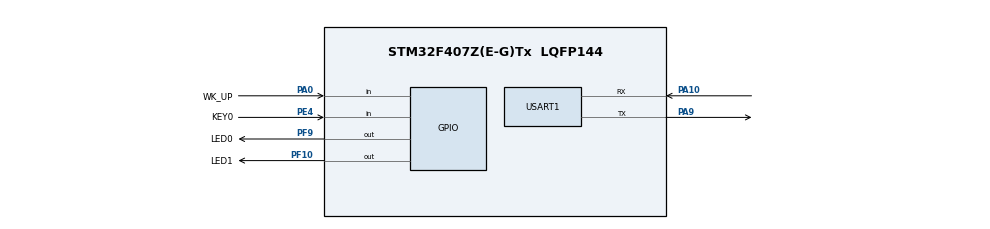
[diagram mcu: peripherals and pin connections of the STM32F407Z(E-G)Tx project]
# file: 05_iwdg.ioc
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IWDG.Prescaler=IWDG_PRESCALER_64
IWDG.Reload=500
Mcu.Family=STM32F4
Mcu.Name=STM32F407Z(E-G)Tx
Mcu.Package=LQFP144
NVIC.PriorityGroup=NVIC_PRIORITYGROUP_2
NVIC.USART1_IRQn=true\:2\:2\:true\:false\:true\:true\:true\:true
PA0-WKUP.GPIO_Label=WK_UP
PA0-WKUP.GPIO_PuPd=GPIO_PULLDOWN
PA0-WKUP.Signal=GPIO_Input
PA10.GPIO_PuPd=GPIO_PULLUP
PA10.Mode=Asynchronous
PA10.Signal=USART1_RX
PA13.Mode=Serial_Wire
PA13.Signal=SYS_JTMS-SWDIO
PA14.Mode=Serial_Wire
PA14.Signal=SYS_JTCK-SWCLK
PA9.GPIO_PuPd=GPIO_PULLUP
PA9.Mode=Asynchronous
PA9.Signal=USART1_TX
PC14-OSC32_IN.Mode=LSE-External-Oscillator
PC14-OSC32_IN.Signal=RCC_OSC32_IN
PC15-OSC32_OUT.Mode=LSE-External-Oscillator
PC15-OSC32_OUT.Signal=RCC_OSC32_OUT
PE4.GPIO_Label=KEY0
PE4.GPIO_PuPd=GPIO_PULLDOWN
PE4.Signal=GPIO_Input
PF10.GPIO_Label=LED1
PF10.GPIO_PuPd=GPIO_PULLDOWN
PF10.GPIO_Speed=GPIO_SPEED_FREQ_VERY_HIGH
PF10.PinState=GPIO_PIN_SET
PF10.Signal=GPIO_Output
PF9.GPIO_Label=LED0
PF9.GPIO_PuPd=GPIO_PULLDOWN
PF9.GPIO_Speed=GPIO_SPEED_FREQ_VERY_HIGH
PF9.PinState=GPIO_PIN_SET
PF9.Signal=GPIO_Output
PH0-OSC_IN.Mode=HSE-External-Oscillator
PH0-OSC_IN.Signal=RCC_OSC_IN
PH1-OSC_OUT.Mode=HSE-External-Oscillator
PH1-OSC_OUT.Signal=RCC_OSC_OUT
ProjectManager.HeapSize=0x200
ProjectManager.StackSize=0x400
ProjectManager.TargetToolchain=STM32CubeIDE
RCC.48MHZClocksFreq_Value=84000000
RCC.AHBFreq_Value=168000000
RCC.APB1CLKDivider=RCC_HCLK_DIV4
RCC.APB1Freq_Value=42000000
RCC.APB1TimFreq_Value=84000000
RCC.APB2CLKDivider=RCC_HCLK_DIV2
RCC.APB2Freq_Value=84000000
RCC.APB2TimFreq_Value=168000000
RCC.CortexFreq_Value=168000000
RCC.HCLKFreq_Value=168000000
RCC.HSE_VALUE=25000000
RCC.HSI_VALUE=16000000
RCC.PLLM=25
RCC.PLLN=336
RCC.PLLSourceVirtual=RCC_PLLSOURCE_HSE
RCC.SYSCLKFreq_VALUE=168000000
RCC.SYSCLKSource=RCC_SYSCLKSOURCE_PLLCLK
RCC.VCOOutputFreq_Value=336000000
USART1.VirtualMode=VM_ASYNC
VP_IWDG_VS_IWDG.Mode=IWDG_Activate
board=custom

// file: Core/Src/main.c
/* USER CODE BEGIN Header */
/**
 ****************************************************************************************************
 * @file        main.c
 * @author      ALIENTEK
 * @brief       IWDG code
 * @license     Copyright (C) 2020-2032, ALIENTEK
 ****************************************************************************************************
 * @attention
 *
 * platform     : ALIENTEK M144-STM32F407 board
 * website      : https://www.alientek.com
 * forum        : http://www.openedv.com/forum.php
 *
 * change logs  :
 * version    data    notes
 * V1.0     20240410  the first version
 *
 ****************************************************************************************************
 */
/* USER CODE END Header */
#include "main.h"
#include "iwdg.h"
#include "usart.h"
#include "gpio.h"

/* USER CODE BEGIN Includes */
#include "../../BSP/LED/led.h"
#include "../../BSP/KEY/key.h"
#include "../../SYSTEM/delay/delay.h"
/* USER CODE END Includes */

void SystemClock_Config(void);

int main(void)
{

  /* MCU Configuration--------------------------------------------------------*/

  /* Reset of all peripherals, Initializes the Flash interface and the Systick. */
  HAL_Init();

  /* Configure the system clock */
  SystemClock_Config();

  /* USER CODE BEGIN SysInit */
  delay_init(168);
  /* USER CODE END SysInit */

  /* Initialize all configured peripherals */
  MX_GPIO_Init();
  MX_USART1_UART_Init();
  MX_IWDG_Init();
  /* USER CODE BEGIN 2 */

  HAL_Delay(100);   		 		/* delay 100ms */
  LED0(0);                    		/* turn on LED0 */

  /* USER CODE END 2 */

  /* Infinite loop */
  while (1)
  {
	  if (key_scan(0) == WKUP_PRES)	/* If WK_UP is pressed, the dog is fed */
	  {
		  iwdg_feed();				/* feed the dog */
	  }

	  delay_ms(10);					/* delay 10ms */
  }
}

void SystemClock_Config(void)
{
  RCC_OscInitTypeDef RCC_OscInitStruct = {0};
  RCC_ClkInitTypeDef RCC_ClkInitStruct = {0};

  /** Configure the main internal regulator output voltage
  */
  __HAL_RCC_PWR_CLK_ENABLE();
  __HAL_PWR_VOLTAGESCALING_CONFIG(PWR_REGULATOR_VOLTAGE_SCALE1);

  /** Initializes the RCC Oscillators according to the specified parameters
  * in the RCC_OscInitTypeDef structure.
  */
  RCC_OscInitStruct.OscillatorType = RCC_OSCILLATORTYPE_LSI|RCC_OSCILLATORTYPE_HSE;
  RCC_OscInitStruct.HSEState = RCC_HSE_ON;
  RCC_OscInitStruct.PLL.PLLState = RCC_PLL_ON;
  RCC_OscInitStruct.PLL.PLLSource = RCC_PLLSOURCE_HSE;
  RCC_OscInitStruct.PLL.PLLM = 8;
  RCC_OscInitStruct.PLL.PLLN = 336;
  RCC_OscInitStruct.PLL.PLLP = RCC_PLLP_DIV2;
  RCC_OscInitStruct.PLL.PLLQ = 7;
  if (HAL_RCC_OscConfig(&RCC_OscInitStruct) != HAL_OK)
  {
    Error_Handler();
  }

  /** Initializes the CPU, AHB and APB buses clocks
  */
  RCC_ClkInitStruct.ClockType = RCC_CLOCKTYPE_HCLK|RCC_CLOCKTYPE_SYSCLK
                              |RCC_CLOCKTYPE_PCLK1|RCC_CLOCKTYPE_PCLK2;
  RCC_ClkInitStruct.SYSCLKSource = RCC_SYSCLKSOURCE_PLLCLK;
  RCC_ClkInitStruct.AHBCLKDivider = RCC_SYSCLK_DIV1;
  RCC_ClkInitStruct.APB1CLKDivider = RCC_HCLK_DIV4;
  RCC_ClkInitStruct.APB2CLKDivider = RCC_HCLK_DIV2;

  if (HAL_RCC_ClockConfig(&RCC_ClkInitStruct, FLASH_LATENCY_5) != HAL_OK)
  {
    Error_Handler();
  }
}

void Error_Handler(void)
{
  __disable_irq();
  while (1)
  {
  }
}
